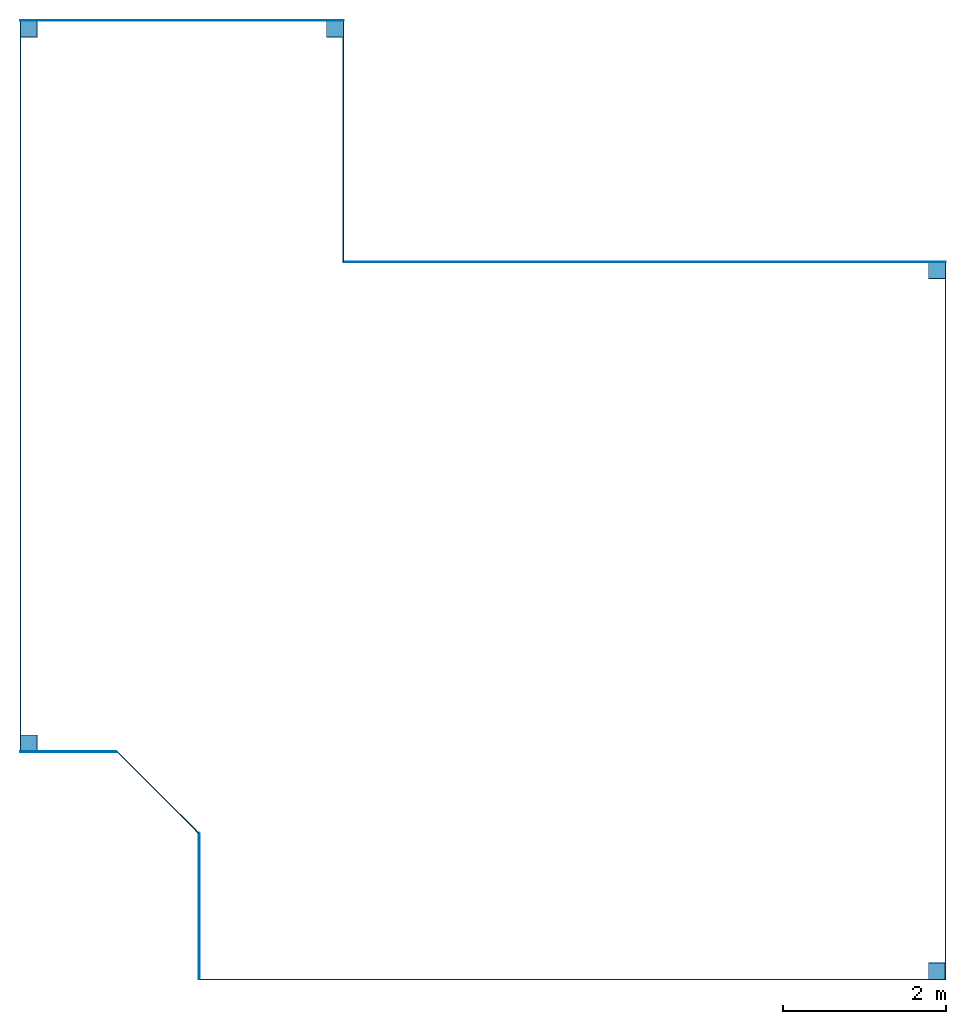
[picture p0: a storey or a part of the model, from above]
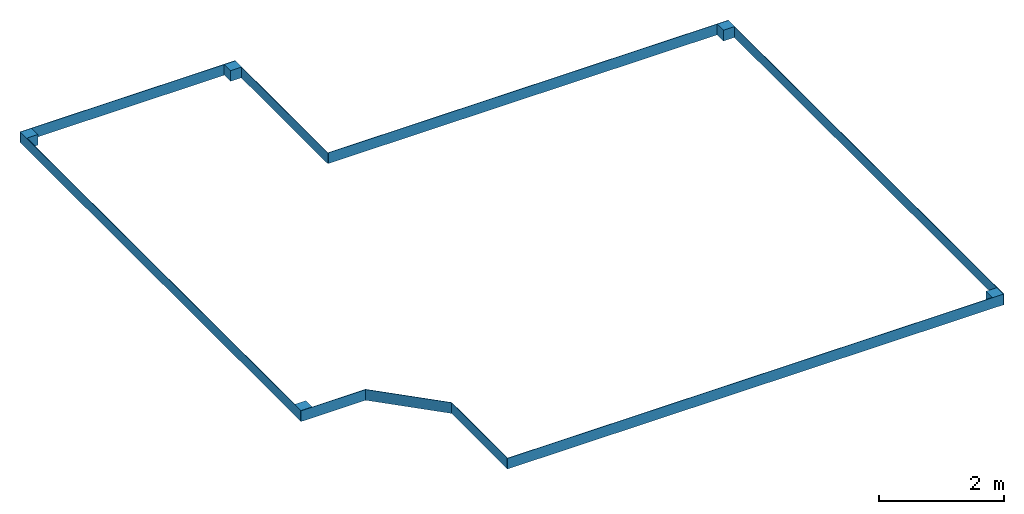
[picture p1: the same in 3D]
Properties of the parts of a building model (IFC2X3)

# File
Description: ViewDefinition [CoordinationView_V2.0]
File name: Numéro du projet
Time: 2023-03-28T11:23:49
Author: VLT22
Organization: Lycée FREYSSINET
Written by: The EXPRESS Data Manager Version 5.02.0100.07 : 28 Aug 2013
Made in: 22.0.2.392 - Exporter 22.0.2.392 - Interface utilisateur alternative 22.0.2.392
Comment: STEP Physical File produced by: The EXPRESS Data Manager Version 5.02.0100.07 : 28 Aug 2013 * Module: EDMstepFileFactory/EDMstandAlone * Creation date: Tue Mar 28 11:23:49 2023 * Host: 220060W-D021X16 * Database: C:\Users\vletiec\AppData\Local\Temp\64bc15eb-90f6-472c-b9ef-01e45360ede1\5d8f2d8c-97d7-4966-9ded-955ce20891aa\ifc * Database version: 5507 * Database creation date: Tue Mar 28 11:23:44 2023 * Schema: IFC2X3 * Model: DataRepository.ifc * Model creation date: Tue Mar 28 11:23:44 2023 * Header model: DataRepository.ifc_HeaderModel * Header model creation date: Tue Mar 28 11:23:44 2023 * EDMuser: sdai-user * EDMgroup: sdai-group * License ID and type: 5605 : Permanent license. Expiry date: * EDMstepFileFactory options: 020000

# IfcProject, Numéro du projet
LongName: Nom du projet; Phase: Etat du projet

# IfcSite, Surface:351218
RefLatitude: 48, 51, 23, 999633; RefLongitude: 2, 21, 3, 553905; RefElevation: 0 cm

# IfcBuilding
Pset_BuildingCommon - NumberOfStoreys: 11

# IfcBuildingStorey: Niveau:Ligne du Niveau (11)
Name | LongName | Elevation (cm)
0_Fondation | 0_Fondation | -98
-0.29_Dessous plancher | -0.29_Dessous plancher | -29
-0.08_Dessus plancher | -0.08_Dessus plancher | -8
1_Rez-de-chaussée | 1_Rez-de-chaussée | -7.93413e-11
2.40_Dessous plafond | 2.40_Dessous plafond | 240
2.57_Dessus dalle | 2.57_Dessus dalle | 257
2.63_Etage | 2.63_Etage | 263
2.82_Arase acrotère | 2.82_Arase acrotère | 282
3.65_Sablière | 3.65_Sablière | 365
5.03_Dessous plafond | 5.03_Dessous plafond | 503
5.67_Arase lucarne | 5.67_Arase lucarne | 567

# IfcSpace: Bains 2 13:360703, 13
In: 2.63_Etage
LongName: Bains 2; InteriorOrExteriorSpace: INTERNAL
Pset_SpaceCommon - Reference: Bains 2 13; FloorCovering: Grès émaillé 30/30 coloris beige

# IfcSpace: Bureau 15:363059, 15
In: 1_Rez-de-chaussée
LongName: Bureau; InteriorOrExteriorSpace: INTERNAL
Pset_SpaceCommon - Reference: Bureau 15; FloorCovering: Parquet

# IfcSpace: Chambre 1 16:363060, 16
In: 1_Rez-de-chaussée
LongName: Chambre 1; InteriorOrExteriorSpace: INTERNAL
Pset_SpaceCommon - Reference: Chambre 1 16; FloorCovering: Parquet

# IfcSpace: Chambre 2 11:360696, 11
In: 2.63_Etage
LongName: Chambre 2; InteriorOrExteriorSpace: INTERNAL
Pset_SpaceCommon - Reference: Chambre 2 11; FloorCovering: Moquette bouclée

# IfcSpace: Chambre 3 12:360700, 12
In: 2.63_Etage
LongName: Chambre 3; InteriorOrExteriorSpace: INTERNAL
Pset_SpaceCommon - Reference: Chambre 3 12; FloorCovering: Moquette bouclée

# IfcSpace: Cuisine 20:363064, 20
In: 1_Rez-de-chaussée
LongName: Cuisine; InteriorOrExteriorSpace: INTERNAL
Pset_SpaceCommon - Reference: Cuisine 20; FloorCovering: Grès émaillé 30/30 coloris gris

# IfcSpace: Dégagement 23:363067, 23
In: 1_Rez-de-chaussée
LongName: Dégagement; InteriorOrExteriorSpace: INTERNAL
Pset_SpaceCommon - Reference: Dégagement 23; FloorCovering: Grès émaillé 30/30 coloris jaune

# IfcSpace: Entrée 21:363065, 21
In: 1_Rez-de-chaussée
LongName: Entrée; InteriorOrExteriorSpace: INTERNAL
Pset_SpaceCommon - Reference: Entrée 21; FloorCovering: Grès émaillé 30/30 coloris jaune

# IfcSpace: Mezzanine 14:360706, 14
In: 2.63_Etage
LongName: Mezzanine; InteriorOrExteriorSpace: INTERNAL
Pset_SpaceCommon - Reference: Mezzanine 14; FloorCovering: Moquette bouclée

# IfcSpace: Rangement 18:363062, 18
In: 1_Rez-de-chaussée
LongName: Rangement; InteriorOrExteriorSpace: INTERNAL
Pset_SpaceCommon - Reference: Rangement 18; FloorCovering: Grès émaillé 30/30 coloris gris

# IfcSpace: Salle de bains 17:363061, 17
In: 1_Rez-de-chaussée
LongName: Salle de bains; InteriorOrExteriorSpace: INTERNAL
Pset_SpaceCommon - Reference: Salle de bains 17; FloorCovering: Grès émaillé 30/30 coloris beige

# IfcSpace: Salon-séjour 22:363066, 22
In: 1_Rez-de-chaussée
LongName: Salon-séjour; InteriorOrExteriorSpace: INTERNAL
Pset_SpaceCommon - Reference: Salon-séjour 22; FloorCovering: Grès émaillé 30/30 coloris jaune

# IfcSpace: WC 19:363063, 19
In: 1_Rez-de-chaussée
LongName: WC; InteriorOrExteriorSpace: INTERNAL
Pset_SpaceCommon - Reference: WC 19; FloorCovering: Grès émaillé 30/30 coloris gris

# IfcBuildingElementProxy: 306233
In: 0_Fondation
Pset_ProvisionForVoid - Shape: Undefined; Width: 114 cm; Depth: 114 cm

# IfcBuildingElementProxy: 306311
In: 0_Fondation
Pset_ProvisionForVoid - Shape: Undefined; Width: 87 cm; Depth: 87 cm

# IfcBuildingElementProxy: 306359
In: 0_Fondation
Pset_ProvisionForVoid - Shape: Undefined; Width: 67 cm; Depth: 67 cm

# IfcBuildingElementProxy: 306388
In: 0_Fondation
Pset_ProvisionForVoid - Shape: Undefined; Width: 67 cm; Depth: 67 cm

# IfcBuildingElementProxy: 306447
In: 0_Fondation
Pset_ProvisionForVoid - Shape: Undefined; Width: 346 cm; Depth: 346 cm

# IfcCovering: Plafond composé:Plafond avec isolation, Plafond composé:Plafond avec isolation:357059
In: 2.63_Etage
Type - PredefinedType: CEILING
Type - Pset_CoveringCommon - TotalThickness: 7 cm
Material: Maçonnerie - Isolant 5 cm, Faux-plafond - Trame 600 x 600 2 cm
Pset_CoveringCommon - Reference: Plafond composé:Plafond avec isolation
Pset_QuantityTakeOff - Reference: Plafond composé:Plafond avec isolation

# IfcDoor: Int. Simple:PP (0.73m x 2.04m) (3)
Type - ParameterTakesPrecedence: no; Sizeable: no; Material: Bois - Cadre de porte, Finition Peinture - Blanc satiné, Bois - Panneau de porte
Type - Pset_DoorCommon - IsExternal: no; ThermalTransmittance: 3.7021 kg/K/s3
OverallHeight: 207.5 cm; OverallWidth: 80 cm; Material: Finition Peinture - Blanc satiné, Bois - Panneau de porte, Bois - Cadre de porte
Pset_DoorCommon - Reference: Int. Simple:PP (0.73m x 2.04m)
Pset_QuantityTakeOff - Reference: Int. Simple:PP (0.73m x 2.04m)
Name (Int. Simple:PP (0.73m x 2.04m):...) | In
355696 | 1_Rez-de-chaussée
360443 | 2.63_Etage
360469 | 2.63_Etage

# IfcDoor: Int. Simple:PP (0.73m x 2.04m) (3)
Type - ParameterTakesPrecedence: no; Sizeable: no; Material: Finition Peinture - Blanc satiné, Bois - Cadre de porte, Bois - Panneau de porte
Type - Pset_DoorCommon - IsExternal: no; ThermalTransmittance: 3.7021 kg/K/s3
OverallHeight: 207.5 cm; OverallWidth: 80 cm; Material: Finition Peinture - Blanc satiné, Bois - Panneau de porte, Bois - Cadre de porte
Pset_DoorCommon - Reference: Int. Simple:PP (0.73m x 2.04m)
Pset_QuantityTakeOff - Reference: Int. Simple:PP (0.73m x 2.04m)
Name (Int. Simple:PP (0.73m x 2.04m):...) | In
356022 | 1_Rez-de-chaussée
356371 | 1_Rez-de-chaussée
360406 | 2.63_Etage

# IfcDoor: Int. Simple:PP (0.83m x 2.04m), Int. Simple:PP (0.83m x 2.04m):355812
In: 1_Rez-de-chaussée
Type - ParameterTakesPrecedence: no; Sizeable: no; Material: Bois - Cadre de porte, Finition Peinture - Blanc satiné, Bois - Panneau de porte
Type - Pset_DoorCommon - IsExternal: no; ThermalTransmittance: 3.7021 kg/K/s3
OverallHeight: 207.5 cm; OverallWidth: 90 cm; Material: Finition Peinture - Blanc satiné, Bois - Panneau de porte, Bois - Cadre de porte
Pset_DoorCommon - Reference: Int. Simple:PP (0.83m x 2.04m)
Pset_QuantityTakeOff - Reference: Int. Simple:PP (0.83m x 2.04m)

# IfcDoor: Int. Simple:PP (0.83m x 2.04m), Int. Simple:PP (0.83m x 2.04m):355748
In: 1_Rez-de-chaussée
Type - ParameterTakesPrecedence: no; Sizeable: no; Material: Finition Peinture - Blanc satiné, Bois - Cadre de porte, Bois - Panneau de porte
Type - Pset_DoorCommon - IsExternal: no; ThermalTransmittance: 3.7021 kg/K/s3
OverallHeight: 207.5 cm; OverallWidth: 90 cm; Material: Finition Peinture - Blanc satiné, Bois - Panneau de porte, Bois - Cadre de porte
Pset_DoorCommon - Reference: Int. Simple:PP (0.83m x 2.04m)
Pset_QuantityTakeOff - Reference: Int. Simple:PP (0.83m x 2.04m)

# IfcDoor: Porte d'entrée gris:90 x 215 cm, Porte d'entrée gris:90 x 215 cm:349865
In: 1_Rez-de-chaussée
Type - ParameterTakesPrecedence: no; Sizeable: no; Classification: B2030130 Exterior Glazed Doors - Wood (Uniformat); Material: Zinc
Type - Pset_DoorCommon - IsExternal: no
Type - Pset_ManufacturerTypeInformation - Manufacturer: Karona , Inc.
OverallHeight: 218.81 cm; OverallWidth: 97.62 cm; Material: Zinc, Wood, Cherry - Grain Vertical
Pset_DoorCommon - Reference: Porte d'entrée gris:90 x 215 cm
Pset_QuantityTakeOff - Reference: Porte d'entrée gris:90 x 215 cm

# IfcDoor: VLT17 Entrée:PP Avec moulures (0.90 m x 2.15 m), VLT17 Entrée:PP Avec moulures (0.90 m x 2.15 m):349838
In: 1_Rez-de-chaussée
Type - OperationType: SINGLE_SWING_LEFT; ParameterTakesPrecedence: no; Sizeable: no; Material: Porte d'entrée - Poignée(1), Porte d'entrée - Panneau(1), Peinture - Noir
Type - VLT17 Entrée:PP Avec moulures (0.90 m x 2.15 m):349838:1 - PanelOperation: SWINGING
Type - Pset_DoorCommon - IsExternal: yes; ThermalTransmittance: 5.5617 kg/K/s3
OverallHeight: 219 cm; OverallWidth: 98 cm; Material: Porte d'entrée - Poignée(1), Porte d'entrée - Panneau(1)
Pset_DoorCommon - Reference: VLT17 Entrée:PP Avec moulures (0.90 m x 2.15 m)
Pset_QuantityTakeOff - Reference: VLT17 Entrée:PP Avec moulures (0.90 m x 2.15 m)

# IfcFooting: Semelle filante:Semelle 45 x 25 (9)
In: 0_Fondation
PredefinedType: STRIP_FOOTING; Material: Maçonnerie - Béton
Pset_QuantityTakeOff - Reference: Semelle filante:Semelle 45 x 25; sets with these values: 3
Name (Semelle filante:Semelle 45 x 25:...)
305962
305980
305998
306016
306030
306048
306066
306084
306102

# IfcFooting: Semelle filante:Semelle 45 x 25 refend (5)
In: 0_Fondation
PredefinedType: STRIP_FOOTING; Material: Maçonnerie - Béton
Pset_QuantityTakeOff - Reference: Semelle filante:Semelle 45 x 25 refend; sets with these values: 3
Name (Semelle filante:Semelle 45 x 25 refend:...)
306509
306563
306585
306607
306629

# IfcOpeningElement: Opening (90)
Name | In | Reference | sets with these values
Mur de base:Cloison 7cm:360087 | 3.65_Sablière
Mur de base:Mur 20:300279 | -0.08_Dessus plancher | 1 Vantail - Droit blanc:140/90 | 2
Mur de base:Mur 20:300304 | -0.08_Dessus plancher | PF 1 Vantail - Droite blanc:80/210 | 2
Mur de base:Mur 20:300374 | -0.08_Dessus plancher | PF 2 Vantaux - Droits blanc:240/210 | 2
Mur de base:Mur 20:300374 | -0.08_Dessus plancher | PF 1 Vantail - Droite blanc:160/210 | 2
Mur de base:Mur 20:300374 | -0.08_Dessus plancher | PF 1 Vantail - Droite blanc:180/210 | 2
Mur de base:Mur 20:300423 | -0.08_Dessus plancher | PF 1 Vantail - Droite blanc:180/210 | 2
Mur de base:Mur 20:300423 | -0.08_Dessus plancher | 2 Vantaux coulissants - Droits blanc:140/80 | 2
2 x Mur de base:Mur 20:300475 | -0.08_Dessus plancher | 1 Vantail - Droit blanc:60/80 | 2
Mur de base:Mur 20:300475 | -0.08_Dessus plancher | 2 Vantaux coulissants - Droits blanc:140/80 | 2
Mur de base:Mur 20:300514 | -0.08_Dessus plancher | Porte d'entrée gris:90 x 215 cm | 2 | Pset_ManufacturerTypeInformation - Manufacturer: Karona , Inc.
Mur de base:Mur 20:300790 | -0.08_Dessus plancher | VLT17 Entrée:PP Avec moulures (0.90 m x 2.15 m) | 2
Sol:Plancher 12+4:302912:2 | 2.57_Dessus dalle | Sol:Plancher 12+4 | 2
Radier:Béton de propreté 5cm:306743:2 | 0_Fondation | Radier:Béton de propreté 5cm | 2
Mur de base:Enduit 2:316493 | 1_Rez-de-chaussée | Porte d'entrée gris:90 x 215 cm | 2 | Pset_ManufacturerTypeInformation - Manufacturer: Karona , Inc.
Mur de base:Enduit 2:316689 | 1_Rez-de-chaussée | Porte d'entrée gris:90 x 215 cm | 2 | Pset_ManufacturerTypeInformation - Manufacturer: Karona , Inc.
2 x Mur de base:Enduit 2:316894 | 1_Rez-de-chaussée | 1 Vantail - Droit blanc:60/80 | 2
Mur de base:Enduit 2:316894 | 1_Rez-de-chaussée | 2 Vantaux coulissants - Droits blanc:140/80 | 2
Mur de base:Cloison 7cm:360087 | 2.82_Arase acrotère
Mur de base:Enduit 2:317087 | 1_Rez-de-chaussée | PF 1 Vantail - Droite blanc:180/210 | 2
Mur de base:Enduit 2:317087 | 1_Rez-de-chaussée | 2 Vantaux coulissants - Droits blanc:140/80 | 2
Mur de base:Enduit 2:317321 | 1_Rez-de-chaussée | PF 2 Vantaux - Droits blanc:240/210 | 2
Mur de base:Enduit 2:317321 | 1_Rez-de-chaussée | PF 1 Vantail - Droite blanc:160/210 | 2
Mur de base:Enduit 2:317321 | 1_Rez-de-chaussée | PF 1 Vantail - Droite blanc:180/210 | 2
Mur de base:Enduit 2:317584 | 1_Rez-de-chaussée | PF 1 Vantail - Droite blanc:80/210 | 2
Mur de base:Enduit 2:317749 | 1_Rez-de-chaussée | 1 Vantail - Droit blanc:140/90 | 2
Mur de base:Enduit 2:317928 | 1_Rez-de-chaussée | VLT17 Entrée:PP Avec moulures (0.90 m x 2.15 m) | 2
Mur de base:Enduit 2:318737 | 1_Rez-de-chaussée | PF 2 Vantaux - Droits blanc:240/210 | 2
Mur de base:Enduit 2:318737 | 1_Rez-de-chaussée | PF 1 Vantail - Droite blanc:160/210 | 2
Mur de base:Enduit 2:318737 | 1_Rez-de-chaussée | PF 1 Vantail - Droite blanc:180/210 | 2
2 x Mur de base:Enduit 2:318737 | 2.82_Arase acrotère | 2 Vantaux coulissants - Droits blanc:180/80 | 2
2 x Mur de base:Enduit 2:318737 | 3.65_Sablière | 2 Vantaux coulissants - Droits blanc:180/80 | 2
Mur de base:Mur 20:319389 | -0.08_Dessus plancher | PF 2 Vantaux - Droits blanc:240/210 | 2
Mur de base:Mur 20:319389 | -0.08_Dessus plancher | PF 1 Vantail - Droite blanc:160/210 | 2
Mur de base:Mur 20:319389 | -0.08_Dessus plancher | PF 1 Vantail - Droite blanc:180/210 | 2
2 x Mur de base:Enduit 2:325063 | 2.82_Arase acrotère | 2 Vantaux coulissants - Droits blanc:180/80 | 2
Int. Simple:PP (0.73m x 2.04m):360469:1 | 2.63_Etage
2 x Mur de base:Enduit 2:325063 | 3.65_Sablière | 2 Vantaux coulissants - Droits blanc:180/80 | 2
2 x Mur de base:Enduit 2:325186 | 2.82_Arase acrotère | 2 Vantaux coulissants - Droits blanc:180/80 | 2
2 x Mur de base:Enduit 2:325341 | 2.82_Arase acrotère | 2 Vantaux coulissants - Droits blanc:180/80 | 2
2 x Mur de base:Enduit 2:325341 | 3.65_Sablière | 2 Vantaux coulissants - Droits blanc:180/80 | 2
Mur de base:Doublage 16:338369 | -0.08_Dessus plancher | PF 1 Vantail - Droite blanc:180/210 | 2
Mur de base:Doublage 16:339148 | -0.08_Dessus plancher | Porte d'entrée gris:90 x 215 cm | 2 | Pset_ManufacturerTypeInformation - Manufacturer: Karona , Inc.
Mur de base:Doublage 16:339244 | -0.08_Dessus plancher | Porte d'entrée gris:90 x 215 cm | 2 | Pset_ManufacturerTypeInformation - Manufacturer: Karona , Inc.
Mur de base:Doublage 16:339502 | -0.08_Dessus plancher | VLT17 Entrée:PP Avec moulures (0.90 m x 2.15 m) | 2
2 x Mur de base:Cloison 7cm:359678 | 3.65_Sablière
2 x Mur de base:Doublage 16:359220 | 2.82_Arase acrotère | 2 Vantaux coulissants - Droits blanc:180/80 | 2
2 x Mur de base:Doublage 16:359220 | 3.65_Sablière | 2 Vantaux coulissants - Droits blanc:180/80 | 2
Mur de base:Mur 20:300988 | -0.08_Dessus plancher
Porte d'entrée gris:90 x 215 cm:349865:1 | -0.08_Dessus plancher
2 x Mur de base:Mur 20:318510 | 2.82_Arase acrotère
2 x Mur de base:Mur 20:318510 | 3.65_Sablière
Mur de base:Mur 20:320650 | -0.08_Dessus plancher
Mur de base:Doublage 16:338058 | -0.08_Dessus plancher
Mur de base:Doublage 16:338229 | -0.08_Dessus plancher
2 x Mur de base:Doublage 16:338369 | -0.08_Dessus plancher
2 x Mur de base:Doublage 16:338818 | -0.08_Dessus plancher
3 x Mur de base:Doublage 16:339035 | -0.08_Dessus plancher
Mur de base:Cloison 7cm:354062 | -0.08_Dessus plancher
Int. Simple:PP (0.83m x 2.04m):355748:1 | -0.08_Dessus plancher
Mur de base:Cloison 7cm:354773 | -0.08_Dessus plancher
Int. Simple:PP (0.83m x 2.04m):355812:1 | -0.08_Dessus plancher
Mur de base:Cloison 7cm:355160 | -0.08_Dessus plancher
Int. Simple:PP (0.73m x 2.04m):356371:1 | -0.08_Dessus plancher
Mur de base:Cloison 7cm:355374 | -0.08_Dessus plancher
Int. Simple:PP (0.73m x 2.04m):355696:1 | -0.08_Dessus plancher
Mur de base:Cloison 7cm:355991 | -0.08_Dessus plancher
Int. Simple:PP (0.73m x 2.04m):356022:1 | -0.08_Dessus plancher
Int. Simple:PP (0.73m x 2.04m):360406:1 | 2.63_Etage
2 x Mur de base:Cloison 7cm:359678 | 2.82_Arase acrotère
Int. Simple:PP (0.73m x 2.04m):360443:1 | 2.63_Etage

# IfcRoof: Toit de base:Toiture (2)
Pset_QuantityTakeOff - Reference: Toit de base:Toiture
Pset_RoofCommon - IsExternal: yes; Reference: Toit de base:Toiture
Name (Toit de base:Toiture:...) | In | ProjectedArea (m2) | TotalArea (m2)
320945 | 3.65_Sablière | 45.0658 | 56.1636 | Material: Ardoise 10 cm
322068 | 5.67_Arase lucarne | 14.1831 | 14.2178

# IfcSlab: Radier:Béton de propreté 5cm, Radier:Béton de propreté 5cm:306743:6
In: 0_Fondation
Type - PredefinedType: BASESLAB; Material: Maçonnerie - Béton(2) 5 cm
Type - Pset_SlabCommon - IsExternal: no
Pset_QuantityTakeOff - Reference: Radier:Béton de propreté 5cm; sets with these values: 2
Pset_SlabCommon - PitchAngle: 0 deg; Reference: Radier:Béton de propreté 5cm; LoadBearing: yes

# IfcSlab: Radier:Béton de propreté 5cm (5)
In: 0_Fondation
Type - PredefinedType: BASESLAB
Type - Pset_SlabCommon - IsExternal: no
Material: Maçonnerie - Béton(2) 5 cm
Pset_QuantityTakeOff - Reference: Radier:Béton de propreté 5cm; sets with these values: 2
Pset_SlabCommon - PitchAngle: 0 deg; Reference: Radier:Béton de propreté 5cm; LoadBearing: yes
Name (Radier:Béton de propreté 5cm:...)
306743
306743:2
306743:3
306743:4
306743:5

# IfcSlab: Sol:Plancher 12+4, Sol:Plancher 12+4:302912
In: 2.57_Dessus dalle
Type - PredefinedType: FLOOR; Material: Maçonnerie - Béton dalle 16 cm
Type - Pset_SlabCommon - IsExternal: no
Pset_QuantityTakeOff - Reference: Sol:Plancher 12+4; sets with these values: 2
Pset_SlabCommon - LoadBearing: no; PitchAngle: 0 deg; Reference: Sol:Plancher 12+4

# IfcSlab: Sol:Plancher 4+12+5, Sol:Plancher 4+12+5:302016
In: -0.08_Dessus plancher
Type - PredefinedType: FLOOR; Material: Maçonnerie - Béton 21 cm
Type - Pset_SlabCommon - IsExternal: no
Pset_QuantityTakeOff - Reference: Sol:Plancher 4+12+5; sets with these values: 2
Pset_SlabCommon - LoadBearing: no; Reference: Sol:Plancher 4+12+5; PitchAngle: 0 deg

# IfcSlab: Toit de base:Toiture, Toit de base:Toiture:322068
In: 5.67_Arase lucarne
Type - PredefinedType: ROOF
Type - Pset_SlabCommon - IsExternal: yes; ThermalTransmittance: 18.83 kg/K/s3
Material: Ardoise 10 cm
Pset_QuantityTakeOff - Reference: Toit de base:Toiture; sets with these values: 2
Pset_SlabCommon - Reference: Toit de base:Toiture; PitchAngle: 4 deg

# IfcWall: Mur de base:Mur de soubassement (3)
In: 0_Fondation
Type - PredefinedType: STANDARD; Material: Protection humidité 1 cm, Blocs de maçonnerie en béton 20 cm
Type - Pset_WallCommon - IsExternal: yes; ThermalTransmittance: 6.15226 kg/K/s3
Pset_QuantityTakeOff - Reference: Mur de base:Mur de soubassement; sets with these values: 2
Pset_WallCommon - LoadBearing: no; Reference: Mur de base:Mur de soubassement; ExtendToStructure: no
Name (Mur de base:Mur de soubassement:...)
305364
305403
305420

# IfcWallStandardCase: Mur de base:Bardage zinc (4)
Type - PredefinedType: STANDARD; Material: Zinc 2 cm
Type - Pset_WallCommon - IsExternal: yes; ThermalTransmittance: 5650 kg/K/s3
Pset_QuantityTakeOff - Reference: Mur de base:Bardage zinc; sets with these values: 2
Pset_WallCommon - LoadBearing: no; ExtendToStructure: no; Reference: Mur de base:Bardage zinc
Name (Mur de base:Bardage zinc:...) | In
326374 | 3.65_Sablière
326374 | 5.03_Dessous plafond
326549 | 3.65_Sablière
326549 | 5.03_Dessous plafond

# IfcWallStandardCase: Mur de base:Cloison 7cm (42)
Type - PredefinedType: STANDARD; Material: Mur par défaut 7 cm
Type - Pset_WallCommon - IsExternal: no
Pset_QuantityTakeOff - Reference: Mur de base:Cloison 7cm; sets with these values: 2
Pset_WallCommon - LoadBearing: no; Reference: Mur de base:Cloison 7cm
Name (Mur de base:Cloison 7cm:...) | In | ExtendToStructure
353536 | -0.08_Dessus plancher | no
354062 | -0.08_Dessus plancher | no
354357 | -0.08_Dessus plancher | no
354631 | -0.08_Dessus plancher | no
354700 | -0.08_Dessus plancher | no
354773 | -0.08_Dessus plancher | no
355040 | -0.08_Dessus plancher | no
355096 | -0.08_Dessus plancher | no
355160 | -0.08_Dessus plancher | no
355374 | -0.08_Dessus plancher | no
355601 | -0.08_Dessus plancher | no
355991 | -0.08_Dessus plancher | no
359678 | 2.63_Etage | no
359678 | 2.82_Arase acrotère | no
359678 | 3.65_Sablière | no
359728 | 2.63_Etage | no
359728 | 2.82_Arase acrotère | no
359728 | 3.65_Sablière | no
359776 | 2.63_Etage | no
359776 | 2.82_Arase acrotère | no
359776 | 3.65_Sablière | no
359922 | 2.63_Etage | no
359922 | 2.82_Arase acrotère | no
359922 | 3.65_Sablière | no
360087 | 2.63_Etage | yes
360087 | 2.82_Arase acrotère | yes
360087 | 3.65_Sablière | yes
360087 | 5.03_Dessous plafond | yes
360087 | 5.67_Arase lucarne | yes
360158 | 2.63_Etage | yes
360158 | 2.82_Arase acrotère | yes
360158 | 3.65_Sablière | yes
360209 | 2.63_Etage | no
360209 | 2.82_Arase acrotère | no
360209 | 3.65_Sablière | no
360252 | 2.63_Etage | no
360252 | 2.82_Arase acrotère | no
360252 | 3.65_Sablière | no
360354 | 2.63_Etage | yes
360354 | 2.82_Arase acrotère | yes
360354 | 3.65_Sablière | yes
360354 | 5.03_Dessous plafond | yes

# IfcWallStandardCase: Mur de base:Doublage 16 (25)
Type - PredefinedType: STANDARD; Material: Isolant rigide 16 cm
Type - Pset_WallCommon - IsExternal: yes; ThermalTransmittance: 0.21875 kg/K/s3
Pset_QuantityTakeOff - Reference: Mur de base:Doublage 16; sets with these values: 2
Pset_WallCommon - LoadBearing: no; Reference: Mur de base:Doublage 16
Name (Mur de base:Doublage 16:...) | In | ExtendToStructure
338058 | -0.08_Dessus plancher | no
338229 | -0.08_Dessus plancher | no
338369 | -0.08_Dessus plancher | no
338818 | -0.08_Dessus plancher | no
339035 | -0.08_Dessus plancher | no
339148 | -0.08_Dessus plancher | no
339244 | -0.08_Dessus plancher | no
339315 | -0.08_Dessus plancher | no
339502 | -0.08_Dessus plancher | no
358559 | 2.63_Etage | yes
358559 | 2.82_Arase acrotère | yes
358559 | 3.65_Sablière | yes
358559 | 5.03_Dessous plafond | yes
358559 | 5.67_Arase lucarne | yes
358711 | 2.63_Etage | yes
358711 | 2.82_Arase acrotère | yes
358711 | 3.65_Sablière | yes
358836 | 2.63_Etage | yes
358836 | 2.82_Arase acrotère | yes
358836 | 3.65_Sablière | yes
358836 | 5.03_Dessous plafond | yes
358836 | 5.67_Arase lucarne | yes
359220 | 2.63_Etage | yes
359220 | 2.82_Arase acrotère | yes
359220 | 3.65_Sablière | yes

# IfcWallStandardCase: Mur de base:Enduit 2 (66)
Type - PredefinedType: STANDARD; Material: Maçonnerie - Enduit 2 cm
Type - Pset_WallCommon - IsExternal: yes
Pset_QuantityTakeOff - Reference: Mur de base:Enduit 2; sets with these values: 2
Pset_WallCommon - LoadBearing: no; Reference: Mur de base:Enduit 2
Name (Mur de base:Enduit 2:...) | In | ExtendToStructure
316278 | 1_Rez-de-chaussée | yes
316278 | 2.40_Dessous plafond | yes
316278 | 2.57_Dessus dalle | yes
316278 | 2.63_Etage | yes
316278 | 2.82_Arase acrotère | yes
316493 | 1_Rez-de-chaussée | no
316493 | 2.40_Dessous plafond | no
316493 | 2.57_Dessus dalle | no
316493 | 2.63_Etage | no
316689 | 1_Rez-de-chaussée | no
316689 | 2.40_Dessous plafond | no
316689 | 2.57_Dessus dalle | no
316689 | 2.63_Etage | no
316894 | 1_Rez-de-chaussée | no
316894 | 2.40_Dessous plafond | no
316894 | 2.57_Dessus dalle | no
316894 | 2.63_Etage | no
317087 | 1_Rez-de-chaussée | no
317087 | 2.40_Dessous plafond | no
317087 | 2.57_Dessus dalle | no
317087 | 2.63_Etage | no
317321 | 1_Rez-de-chaussée | no
317321 | 2.40_Dessous plafond | no
317321 | 2.57_Dessus dalle | no
317321 | 2.63_Etage | no
317584 | 1_Rez-de-chaussée | no
317584 | 2.40_Dessous plafond | no
317584 | 2.57_Dessus dalle | no
317584 | 2.63_Etage | no
317749 | 1_Rez-de-chaussée | no
317749 | 2.40_Dessous plafond | no
317749 | 2.57_Dessus dalle | no
317749 | 2.63_Etage | no
317928 | 1_Rez-de-chaussée | no
317928 | 2.40_Dessous plafond | no
317928 | 2.57_Dessus dalle | no
317928 | 2.63_Etage | no
318737 | 1_Rez-de-chaussée | yes
318737 | 2.40_Dessous plafond | yes
318737 | 2.57_Dessus dalle | yes
318737 | 2.63_Etage | yes
318737 | 2.82_Arase acrotère | yes
318737 | 3.65_Sablière | yes
318737 | 5.03_Dessous plafond | yes
324332 | 2.63_Etage | yes
324332 | 2.82_Arase acrotère | yes
324332 | 3.65_Sablière | yes
324332 | 5.03_Dessous plafond | yes
324332 | 5.67_Arase lucarne | yes
324603 | 2.63_Etage | yes
324603 | 2.82_Arase acrotère | yes
324839 | 2.82_Arase acrotère | yes
324839 | 3.65_Sablière | yes
325063 | 2.82_Arase acrotère | yes
325063 | 3.65_Sablière | yes
325063 | 5.03_Dessous plafond | yes
325186 | 2.82_Arase acrotère | yes
325341 | 2.63_Etage | yes
325341 | 2.82_Arase acrotère | yes
325341 | 3.65_Sablière | yes
325341 | 5.03_Dessous plafond | yes
325818 | 2.82_Arase acrotère | yes
351077 | 2.82_Arase acrotère | yes
351077 | 3.65_Sablière | yes
351077 | 5.03_Dessous plafond | yes
351077 | 5.67_Arase lucarne | yes

# IfcWallStandardCase: Mur de base:Mur 20 (23)
Type - PredefinedType: STANDARD; Material: Maçonnerie - Béton 20 cm
Type - Pset_WallCommon - IsExternal: yes
Pset_QuantityTakeOff - Reference: Mur de base:Mur 20; sets with these values: 2
Pset_WallCommon - Reference: Mur de base:Mur 20; ExtendToStructure: yes; LoadBearing: no
Name (Mur de base:Mur 20:...) | In
300279 | -0.08_Dessus plancher
300304 | -0.08_Dessus plancher
300374 | -0.08_Dessus plancher
300423 | -0.08_Dessus plancher
300475 | -0.08_Dessus plancher
300514 | -0.08_Dessus plancher
300790 | -0.08_Dessus plancher
300898 | -0.08_Dessus plancher
300988 | -0.08_Dessus plancher
318294 | 2.63_Etage
318294 | 2.82_Arase acrotère
318294 | 3.65_Sablière
318510 | 2.63_Etage
318510 | 2.82_Arase acrotère
318510 | 3.65_Sablière
318510 | 5.03_Dessous plafond
319389 | -0.08_Dessus plancher
319563 | 2.63_Etage
319563 | 2.82_Arase acrotère
319563 | 3.65_Sablière
319563 | 5.03_Dessous plafond
319563 | 5.67_Arase lucarne
320650 | -0.08_Dessus plancher

# IfcWallStandardCase: Mur de base:Mur de soubassement (15)
Type - PredefinedType: STANDARD; Material: Protection humidité 1 cm, Blocs de maçonnerie en béton 20 cm
Type - Pset_WallCommon - IsExternal: yes; ThermalTransmittance: 6.15226 kg/K/s3
Pset_QuantityTakeOff - Reference: Mur de base:Mur de soubassement; sets with these values: 2
Pset_WallCommon - LoadBearing: no; Reference: Mur de base:Mur de soubassement; ExtendToStructure: no
Name (Mur de base:Mur de soubassement:...) | In
305063 | 0_Fondation
305063 | -0.29_Dessous plancher
305104 | 0_Fondation
305104 | -0.29_Dessous plancher
305176 | 0_Fondation
305176 | -0.29_Dessous plancher
305253 | 0_Fondation
305253 | -0.29_Dessous plancher
305323 | 0_Fondation
305323 | -0.29_Dessous plancher
305364 | -0.29_Dessous plancher
305403 | -0.29_Dessous plancher
305420 | -0.29_Dessous plancher
305466 | 0_Fondation
305466 | -0.29_Dessous plancher

# IfcWallStandardCase: Mur de base:Mur de soubassement refend (5)
In: 0_Fondation
Type - PredefinedType: STANDARD; Material: Blocs de maçonnerie en béton 20 cm
Type - Pset_WallCommon - IsExternal: yes; ThermalTransmittance: 6.5 kg/K/s3
Pset_QuantityTakeOff - Reference: Mur de base:Mur de soubassement refend; sets with these values: 2
Pset_WallCommon - LoadBearing: no; ExtendToStructure: no; Reference: Mur de base:Mur de soubassement refend
Name (Mur de base:Mur de soubassement refend:...)
306230
306310
306357
306387
306446

# IfcWallStandardCase: Mur de base:Mur refend 22 (5)
In: -0.08_Dessus plancher
Type - PredefinedType: STANDARD; Material: Plâtre 1 cm, Mur par défaut 20 cm, Plâtre 1 cm
Type - Pset_WallCommon - IsExternal: yes; ThermalTransmittance: 25.5 kg/K/s3
Pset_QuantityTakeOff - Reference: Mur de base:Mur refend 22; sets with these values: 2
Pset_WallCommon - ExtendToStructure: yes; LoadBearing: no; Reference: Mur de base:Mur refend 22
Name (Mur de base:Mur refend 22:...)
301366
301477
301562
301671
301788

# IfcWindow: 1 Vantail - Droit blanc:140/90, 1 Vantail - Droit blanc:140/90:339886
In: 1_Rez-de-chaussée
Type - OperationType: SINGLE_PANEL; ParameterTakesPrecedence: no; Sizeable: no; Material: Fenêtre - Vitrage, Fenêtre - Cadre, Fenêtre - Poignée, Fenêtre - Appui
Type - Pset_WindowCommon - IsExternal: no; ThermalTransmittance: 5.5617 kg/K/s3
OverallHeight: 108 cm; OverallWidth: 150 cm; Material: Fenêtre - Poignée, Fenêtre - Appui, Fenêtre - Vitrage, Fenêtre - Cadre
Pset_QuantityTakeOff - Reference: 1 Vantail - Droit blanc:140/90
Pset_WindowCommon - IsExternal: yes; Reference: 1 Vantail - Droit blanc:140/90

# IfcWindow: 1 Vantail - Droit blanc:60/80 (2)
In: 1_Rez-de-chaussée
Type - OperationType: SINGLE_PANEL; ParameterTakesPrecedence: no; Sizeable: no; Material: Fenêtre - Appui, Fenêtre - Cadre, Fenêtre - Poignée, Fenêtre - Vitrage
Type - Pset_WindowCommon - IsExternal: no; ThermalTransmittance: 5.5617 kg/K/s3
OverallHeight: 108 cm; OverallWidth: 70 cm; Material: Fenêtre - Poignée, Fenêtre - Appui, Fenêtre - Vitrage, Fenêtre - Cadre
Pset_QuantityTakeOff - Reference: 1 Vantail - Droit blanc:60/80
Pset_WindowCommon - Reference: 1 Vantail - Droit blanc:60/80
Name (1 Vantail - Droit blanc:60/80:...)
339953 | Pset_WindowCommon - IsExternal: yes
340052

# IfcWindow: 2 Vantaux coulissants - Droits blanc:140/80 (2)
In: 1_Rez-de-chaussée
Type - OperationType: DOUBLE_PANEL_VERTICAL; ParameterTakesPrecedence: no; Sizeable: no; Material: Fenêtre - Cadre, Fenêtre - Vitrage, Fenêtre - Poignée, Fenêtre - Appui
Type - Pset_WindowCommon - IsExternal: no; ThermalTransmittance: 3.6886 kg/K/s3
OverallHeight: 108 cm; OverallWidth: 150 cm; Material: Fenêtre - Poignée, Fenêtre - Appui, Fenêtre - Vitrage, Fenêtre - Cadre
Pset_QuantityTakeOff - Reference: 2 Vantaux coulissants - Droits blanc:140/80
Pset_WindowCommon - Reference: 2 Vantaux coulissants - Droits blanc:140/80
Name (2 Vantaux coulissants - Droits blanc:140/80:...)
340142 | Pset_WindowCommon - IsExternal: yes
352873

# IfcWindow: 2 Vantaux coulissants - Droits blanc:180/80 (2)
In: 2.63_Etage
Type - OperationType: DOUBLE_PANEL_VERTICAL; ParameterTakesPrecedence: no; Sizeable: no; Material: Fenêtre - Vitrage, Fenêtre - Appui, Fenêtre - Cadre, Fenêtre - Poignée
Type - Pset_WindowCommon - IsExternal: no; ThermalTransmittance: 3.6886 kg/K/s3
OverallHeight: 108 cm; OverallWidth: 190 cm; Material: Fenêtre - Poignée, Fenêtre - Appui, Fenêtre - Vitrage, Fenêtre - Cadre
Pset_QuantityTakeOff - Reference: 2 Vantaux coulissants - Droits blanc:180/80
Pset_WindowCommon - Reference: 2 Vantaux coulissants - Droits blanc:180/80
Name (2 Vantaux coulissants - Droits blanc:180/80:...)
350089 | Pset_WindowCommon - IsExternal: yes
350167

# IfcWindow: Fenêtre de toit:114/118, Fenêtre de toit:114/118:362473
In: 3.65_Sablière
Type - ParameterTakesPrecedence: no; Sizeable: no; Material: Ardoise, <Unnamed>
Type - Pset_WindowCommon - IsExternal: no; ThermalTransmittance: 3.6886 kg/K/s3
OverallHeight: 14.5 cm; OverallWidth: 116 cm; Material: <Unnamed>, Ardoise, Fenêtre - Vitrage
Pset_QuantityTakeOff - Reference: Fenêtre de toit:114/118
Pset_WindowCommon - IsExternal: yes; Reference: Fenêtre de toit:114/118

# IfcWindow: Fenêtre de toit:Fenêtre de toit, Fenêtre de toit:Fenêtre de toit:362577
In: 3.65_Sablière
Type - ParameterTakesPrecedence: no; Sizeable: no; Material: <Unnamed>, Ardoise
Type - Pset_WindowCommon - IsExternal: no; ThermalTransmittance: 3.6886 kg/K/s3
OverallHeight: 14.5 cm; OverallWidth: 80 cm; Material: <Unnamed>, Ardoise, Fenêtre - Vitrage
Pset_QuantityTakeOff - Reference: Fenêtre de toit:Fenêtre de toit
Pset_WindowCommon - IsExternal: yes; Reference: Fenêtre de toit:Fenêtre de toit

# IfcWindow: PF 1 Vantail - Droite blanc:160/210, PF 1 Vantail - Droite blanc:160/210:339762
In: 1_Rez-de-chaussée
Type - OperationType: SINGLE_PANEL; ParameterTakesPrecedence: no; Sizeable: no; Material: Fenêtre - Vitrage, Fenêtre - Poignée, Fenêtre - Appui, Fenêtre - Cadre
Type - Pset_WindowCommon - IsExternal: no; ThermalTransmittance: 5.5617 kg/K/s3
OverallHeight: 221.5 cm; OverallWidth: 170 cm; Material: Fenêtre - Poignée, Fenêtre - Appui, Fenêtre - Vitrage, Fenêtre - Cadre
Pset_QuantityTakeOff - Reference: PF 1 Vantail - Droite blanc:160/210
Pset_WindowCommon - IsExternal: yes; Reference: PF 1 Vantail - Droite blanc:160/210

# IfcWindow: PF 1 Vantail - Droite blanc:180/210, PF 1 Vantail - Droite blanc:180/210:339829
In: 1_Rez-de-chaussée
Type - OperationType: SINGLE_PANEL; ParameterTakesPrecedence: no; Sizeable: no; Material: Fenêtre - Cadre, Fenêtre - Appui, Fenêtre - Vitrage, Fenêtre - Poignée
Type - Pset_WindowCommon - IsExternal: no; ThermalTransmittance: 5.5617 kg/K/s3
OverallHeight: 221.5 cm; OverallWidth: 190 cm; Material: Fenêtre - Poignée, Fenêtre - Appui, Fenêtre - Vitrage, Fenêtre - Cadre
Pset_QuantityTakeOff - Reference: PF 1 Vantail - Droite blanc:180/210
Pset_WindowCommon - IsExternal: yes; Reference: PF 1 Vantail - Droite blanc:180/210

# IfcWindow: PF 1 Vantail - Droite blanc:80/210, PF 1 Vantail - Droite blanc:80/210:356459
In: 1_Rez-de-chaussée
Type - OperationType: SINGLE_PANEL; ParameterTakesPrecedence: no; Sizeable: no; Material: Fenêtre - Poignée, Fenêtre - Appui, Fenêtre - Cadre, Fenêtre - Vitrage
Type - Pset_WindowCommon - IsExternal: no; ThermalTransmittance: 5.5617 kg/K/s3
OverallHeight: 221.5 cm; OverallWidth: 90 cm; Material: Fenêtre - Poignée, Fenêtre - Appui, Fenêtre - Vitrage, Fenêtre - Cadre
Pset_QuantityTakeOff - Reference: PF 1 Vantail - Droite blanc:80/210
Pset_WindowCommon - IsExternal: yes; Reference: PF 1 Vantail - Droite blanc:80/210

# IfcWindow: PF 2 Vantaux - Droits blanc:240/210, PF 2 Vantaux - Droits blanc:240/210:339671
In: 1_Rez-de-chaussée
Type - OperationType: DOUBLE_PANEL_VERTICAL; ParameterTakesPrecedence: no; Sizeable: no; Material: Fenêtre - Poignée, Fenêtre - Cadre, Fenêtre - Appui, Fenêtre - Vitrage
Type - Pset_WindowCommon - IsExternal: no; ThermalTransmittance: 3.6886 kg/K/s3
OverallHeight: 221.5 cm; OverallWidth: 250 cm; Material: Fenêtre - Poignée, Fenêtre - Appui, Fenêtre - Cadre, Fenêtre - Vitrage
Pset_QuantityTakeOff - Reference: PF 2 Vantaux - Droits blanc:240/210
Pset_WindowCommon - IsExternal: yes; Reference: PF 2 Vantaux - Droits blanc:240/210
